VERSION 5.7 ;
  NOWIREEXTENSIONATPIN ON ;
  DIVIDERCHAR "/" ;
  BUSBITCHARS "[]" ;
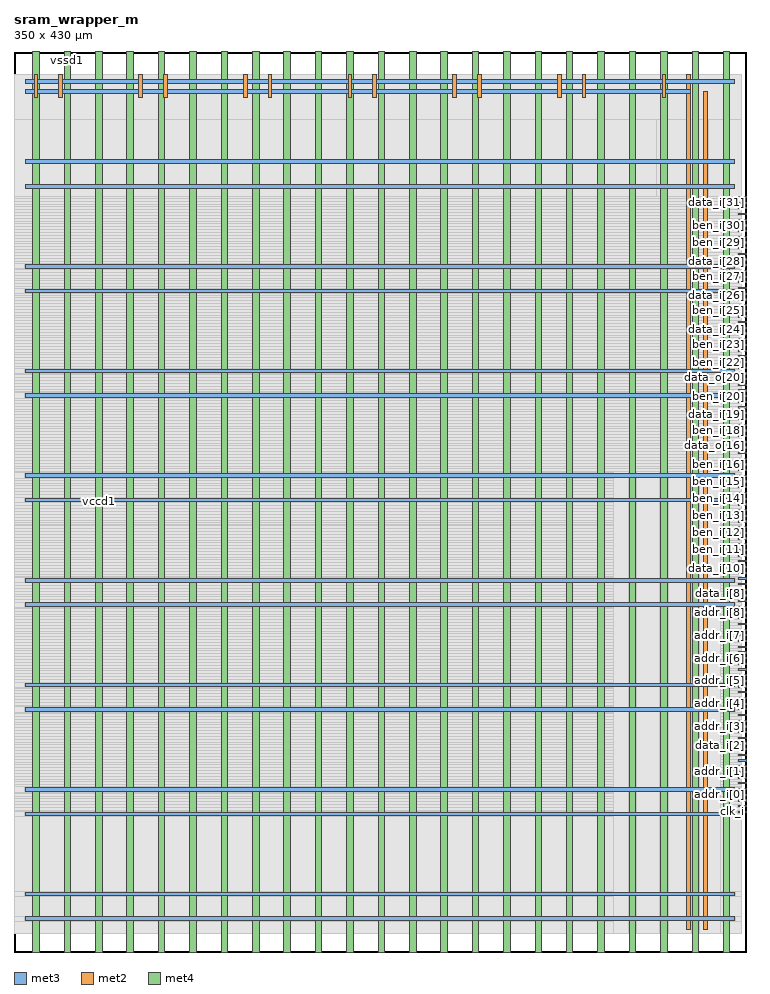
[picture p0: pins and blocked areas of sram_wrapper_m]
MACRO sram_wrapper_m
  CLASS BLOCK ;
  FOREIGN sram_wrapper_m ;
  ORIGIN 0.000 0.000 ;
  SIZE 350.000 BY 430.000 ;
  PIN addr_i[0]
    DIRECTION INPUT ;
    USE SIGNAL ;
    ANTENNAGATEAREA 0.213000 ;
    PORT
      LAYER met3 ;
        RECT 346.000 74.840 350.000 75.440 ;
    END
  END addr_i[0]
  PIN addr_i[1]
    DIRECTION INPUT ;
    USE SIGNAL ;
    ANTENNAGATEAREA 0.213000 ;
    PORT
      LAYER met3 ;
        RECT 346.000 85.720 350.000 86.320 ;
    END
  END addr_i[1]
  PIN addr_i[2]
    DIRECTION INPUT ;
    USE SIGNAL ;
    ANTENNAGATEAREA 0.213000 ;
    PORT
      LAYER met3 ;
        RECT 346.000 96.600 350.000 97.200 ;
    END
  END addr_i[2]
  PIN addr_i[3]
    DIRECTION INPUT ;
    USE SIGNAL ;
    ANTENNAGATEAREA 0.213000 ;
    PORT
      LAYER met3 ;
        RECT 346.000 107.480 350.000 108.080 ;
    END
  END addr_i[3]
  PIN addr_i[4]
    DIRECTION INPUT ;
    USE SIGNAL ;
    ANTENNAGATEAREA 0.159000 ;
    PORT
      LAYER met3 ;
        RECT 346.000 118.360 350.000 118.960 ;
    END
  END addr_i[4]
  PIN addr_i[5]
    DIRECTION INPUT ;
    USE SIGNAL ;
    ANTENNAGATEAREA 0.159000 ;
    PORT
      LAYER met3 ;
        RECT 346.000 129.240 350.000 129.840 ;
    END
  END addr_i[5]
  PIN addr_i[6]
    DIRECTION INPUT ;
    USE SIGNAL ;
    ANTENNAGATEAREA 0.159000 ;
    PORT
      LAYER met3 ;
        RECT 346.000 140.120 350.000 140.720 ;
    END
  END addr_i[6]
  PIN addr_i[7]
    DIRECTION INPUT ;
    USE SIGNAL ;
    ANTENNAGATEAREA 0.159000 ;
    PORT
      LAYER met3 ;
        RECT 346.000 151.000 350.000 151.600 ;
    END
  END addr_i[7]
  PIN addr_i[8]
    DIRECTION INPUT ;
    USE SIGNAL ;
    ANTENNAGATEAREA 0.159000 ;
    PORT
      LAYER met3 ;
        RECT 346.000 161.880 350.000 162.480 ;
    END
  END addr_i[8]
  PIN addr_i[9]
    DIRECTION INPUT ;
    USE SIGNAL ;
    ANTENNAGATEAREA 0.159000 ;
    PORT
      LAYER met3 ;
        RECT 346.000 172.760 350.000 173.360 ;
    END
  END addr_i[9]
  PIN ben_i[0]
    DIRECTION INPUT ;
    USE SIGNAL ;
    ANTENNAGATEAREA 0.159000 ;
    PORT
      LAYER met3 ;
        RECT 346.000 77.560 350.000 78.160 ;
    END
  END ben_i[0]
  PIN ben_i[10]
    DIRECTION INPUT ;
    USE SIGNAL ;
    ANTENNAGATEAREA 0.159000 ;
    PORT
      LAYER met3 ;
        RECT 346.000 183.640 350.000 184.240 ;
    END
  END ben_i[10]
  PIN ben_i[11]
    DIRECTION INPUT ;
    USE SIGNAL ;
    ANTENNAGATEAREA 0.213000 ;
    PORT
      LAYER met3 ;
        RECT 346.000 191.800 350.000 192.400 ;
    END
  END ben_i[11]
  PIN ben_i[12]
    DIRECTION INPUT ;
    USE SIGNAL ;
    ANTENNAGATEAREA 0.213000 ;
    PORT
      LAYER met3 ;
        RECT 346.000 199.960 350.000 200.560 ;
    END
  END ben_i[12]
  PIN ben_i[13]
    DIRECTION INPUT ;
    USE SIGNAL ;
    ANTENNAGATEAREA 0.213000 ;
    PORT
      LAYER met3 ;
        RECT 346.000 208.120 350.000 208.720 ;
    END
  END ben_i[13]
  PIN ben_i[14]
    DIRECTION INPUT ;
    USE SIGNAL ;
    ANTENNAGATEAREA 0.213000 ;
    PORT
      LAYER met3 ;
        RECT 346.000 216.280 350.000 216.880 ;
    END
  END ben_i[14]
  PIN ben_i[15]
    DIRECTION INPUT ;
    USE SIGNAL ;
    ANTENNAGATEAREA 0.213000 ;
    PORT
      LAYER met3 ;
        RECT 346.000 224.440 350.000 225.040 ;
    END
  END ben_i[15]
  PIN ben_i[16]
    DIRECTION INPUT ;
    USE SIGNAL ;
    ANTENNAGATEAREA 0.159000 ;
    PORT
      LAYER met3 ;
        RECT 346.000 232.600 350.000 233.200 ;
    END
  END ben_i[16]
  PIN ben_i[17]
    DIRECTION INPUT ;
    USE SIGNAL ;
    ANTENNAGATEAREA 0.213000 ;
    PORT
      LAYER met3 ;
        RECT 346.000 240.760 350.000 241.360 ;
    END
  END ben_i[17]
  PIN ben_i[18]
    DIRECTION INPUT ;
    USE SIGNAL ;
    ANTENNAGATEAREA 0.213000 ;
    PORT
      LAYER met3 ;
        RECT 346.000 248.920 350.000 249.520 ;
    END
  END ben_i[18]
  PIN ben_i[19]
    DIRECTION INPUT ;
    USE SIGNAL ;
    ANTENNAGATEAREA 0.213000 ;
    PORT
      LAYER met3 ;
        RECT 346.000 257.080 350.000 257.680 ;
    END
  END ben_i[19]
  PIN ben_i[1]
    DIRECTION INPUT ;
    USE SIGNAL ;
    ANTENNAGATEAREA 0.159000 ;
    PORT
      LAYER met3 ;
        RECT 346.000 88.440 350.000 89.040 ;
    END
  END ben_i[1]
  PIN ben_i[20]
    DIRECTION INPUT ;
    USE SIGNAL ;
    ANTENNAGATEAREA 0.213000 ;
    PORT
      LAYER met3 ;
        RECT 346.000 265.240 350.000 265.840 ;
    END
  END ben_i[20]
  PIN ben_i[21]
    DIRECTION INPUT ;
    USE SIGNAL ;
    ANTENNAGATEAREA 0.213000 ;
    PORT
      LAYER met3 ;
        RECT 346.000 273.400 350.000 274.000 ;
    END
  END ben_i[21]
  PIN ben_i[22]
    DIRECTION INPUT ;
    USE SIGNAL ;
    ANTENNAGATEAREA 0.213000 ;
    PORT
      LAYER met3 ;
        RECT 346.000 281.560 350.000 282.160 ;
    END
  END ben_i[22]
  PIN ben_i[23]
    DIRECTION INPUT ;
    USE SIGNAL ;
    ANTENNAGATEAREA 0.213000 ;
    PORT
      LAYER met3 ;
        RECT 346.000 289.720 350.000 290.320 ;
    END
  END ben_i[23]
  PIN ben_i[24]
    DIRECTION INPUT ;
    USE SIGNAL ;
    ANTENNAGATEAREA 0.213000 ;
    PORT
      LAYER met3 ;
        RECT 346.000 297.880 350.000 298.480 ;
    END
  END ben_i[24]
  PIN ben_i[25]
    DIRECTION INPUT ;
    USE SIGNAL ;
    ANTENNAGATEAREA 0.159000 ;
    PORT
      LAYER met3 ;
        RECT 346.000 306.040 350.000 306.640 ;
    END
  END ben_i[25]
  PIN ben_i[26]
    DIRECTION INPUT ;
    USE SIGNAL ;
    ANTENNAGATEAREA 0.159000 ;
    PORT
      LAYER met3 ;
        RECT 346.000 314.200 350.000 314.800 ;
    END
  END ben_i[26]
  PIN ben_i[27]
    DIRECTION INPUT ;
    USE SIGNAL ;
    ANTENNAGATEAREA 0.159000 ;
    PORT
      LAYER met3 ;
        RECT 346.000 322.360 350.000 322.960 ;
    END
  END ben_i[27]
  PIN ben_i[28]
    DIRECTION INPUT ;
    USE SIGNAL ;
    ANTENNAGATEAREA 0.159000 ;
    PORT
      LAYER met3 ;
        RECT 346.000 330.520 350.000 331.120 ;
    END
  END ben_i[28]
  PIN ben_i[29]
    DIRECTION INPUT ;
    USE SIGNAL ;
    ANTENNAGATEAREA 0.159000 ;
    PORT
      LAYER met3 ;
        RECT 346.000 338.680 350.000 339.280 ;
    END
  END ben_i[29]
  PIN ben_i[2]
    DIRECTION INPUT ;
    USE SIGNAL ;
    ANTENNAGATEAREA 0.159000 ;
    PORT
      LAYER met3 ;
        RECT 346.000 99.320 350.000 99.920 ;
    END
  END ben_i[2]
  PIN ben_i[30]
    DIRECTION INPUT ;
    USE SIGNAL ;
    ANTENNAGATEAREA 0.159000 ;
    PORT
      LAYER met3 ;
        RECT 346.000 346.840 350.000 347.440 ;
    END
  END ben_i[30]
  PIN ben_i[31]
    DIRECTION INPUT ;
    USE SIGNAL ;
    ANTENNAGATEAREA 0.159000 ;
    PORT
      LAYER met3 ;
        RECT 346.000 355.000 350.000 355.600 ;
    END
  END ben_i[31]
  PIN ben_i[3]
    DIRECTION INPUT ;
    USE SIGNAL ;
    ANTENNAGATEAREA 0.159000 ;
    PORT
      LAYER met3 ;
        RECT 346.000 110.200 350.000 110.800 ;
    END
  END ben_i[3]
  PIN ben_i[4]
    DIRECTION INPUT ;
    USE SIGNAL ;
    ANTENNAGATEAREA 0.159000 ;
    PORT
      LAYER met3 ;
        RECT 346.000 121.080 350.000 121.680 ;
    END
  END ben_i[4]
  PIN ben_i[5]
    DIRECTION INPUT ;
    USE SIGNAL ;
    ANTENNAGATEAREA 0.213000 ;
    PORT
      LAYER met3 ;
        RECT 346.000 131.960 350.000 132.560 ;
    END
  END ben_i[5]
  PIN ben_i[6]
    DIRECTION INPUT ;
    USE SIGNAL ;
    ANTENNAGATEAREA 0.159000 ;
    PORT
      LAYER met3 ;
        RECT 346.000 142.840 350.000 143.440 ;
    END
  END ben_i[6]
  PIN ben_i[7]
    DIRECTION INPUT ;
    USE SIGNAL ;
    ANTENNAGATEAREA 0.159000 ;
    PORT
      LAYER met3 ;
        RECT 346.000 153.720 350.000 154.320 ;
    END
  END ben_i[7]
  PIN ben_i[8]
    DIRECTION INPUT ;
    USE SIGNAL ;
    ANTENNAGATEAREA 0.159000 ;
    PORT
      LAYER met3 ;
        RECT 346.000 164.600 350.000 165.200 ;
    END
  END ben_i[8]
  PIN ben_i[9]
    DIRECTION INPUT ;
    USE SIGNAL ;
    ANTENNAGATEAREA 0.159000 ;
    PORT
      LAYER met3 ;
        RECT 346.000 175.480 350.000 176.080 ;
    END
  END ben_i[9]
  PIN clk_i
    DIRECTION INPUT ;
    USE SIGNAL ;
    PORT
      LAYER met3 ;
        RECT 346.000 66.680 350.000 67.280 ;
    END
  END clk_i
  PIN data_i[0]
    DIRECTION INPUT ;
    USE SIGNAL ;
    ANTENNAGATEAREA 0.159000 ;
    PORT
      LAYER met3 ;
        RECT 346.000 80.280 350.000 80.880 ;
    END
  END data_i[0]
  PIN data_i[10]
    DIRECTION INPUT ;
    USE SIGNAL ;
    ANTENNAGATEAREA 0.159000 ;
    PORT
      LAYER met3 ;
        RECT 346.000 186.360 350.000 186.960 ;
    END
  END data_i[10]
  PIN data_i[11]
    DIRECTION INPUT ;
    USE SIGNAL ;
    ANTENNAGATEAREA 0.159000 ;
    PORT
      LAYER met3 ;
        RECT 346.000 194.520 350.000 195.120 ;
    END
  END data_i[11]
  PIN data_i[12]
    DIRECTION INPUT ;
    USE SIGNAL ;
    ANTENNAGATEAREA 0.213000 ;
    PORT
      LAYER met3 ;
        RECT 346.000 202.680 350.000 203.280 ;
    END
  END data_i[12]
  PIN data_i[13]
    DIRECTION INPUT ;
    USE SIGNAL ;
    ANTENNAGATEAREA 0.213000 ;
    PORT
      LAYER met3 ;
        RECT 346.000 210.840 350.000 211.440 ;
    END
  END data_i[13]
  PIN data_i[14]
    DIRECTION INPUT ;
    USE SIGNAL ;
    ANTENNAGATEAREA 0.213000 ;
    PORT
      LAYER met3 ;
        RECT 346.000 219.000 350.000 219.600 ;
    END
  END data_i[14]
  PIN data_i[15]
    DIRECTION INPUT ;
    USE SIGNAL ;
    ANTENNAGATEAREA 0.213000 ;
    PORT
      LAYER met3 ;
        RECT 346.000 227.160 350.000 227.760 ;
    END
  END data_i[15]
  PIN data_i[16]
    DIRECTION INPUT ;
    USE SIGNAL ;
    ANTENNAGATEAREA 0.213000 ;
    PORT
      LAYER met3 ;
        RECT 346.000 235.320 350.000 235.920 ;
    END
  END data_i[16]
  PIN data_i[17]
    DIRECTION INPUT ;
    USE SIGNAL ;
    ANTENNAGATEAREA 0.213000 ;
    PORT
      LAYER met3 ;
        RECT 346.000 243.480 350.000 244.080 ;
    END
  END data_i[17]
  PIN data_i[18]
    DIRECTION INPUT ;
    USE SIGNAL ;
    ANTENNAGATEAREA 0.213000 ;
    PORT
      LAYER met3 ;
        RECT 346.000 251.640 350.000 252.240 ;
    END
  END data_i[18]
  PIN data_i[19]
    DIRECTION INPUT ;
    USE SIGNAL ;
    ANTENNAGATEAREA 0.213000 ;
    PORT
      LAYER met3 ;
        RECT 346.000 259.800 350.000 260.400 ;
    END
  END data_i[19]
  PIN data_i[1]
    DIRECTION INPUT ;
    USE SIGNAL ;
    ANTENNAGATEAREA 0.159000 ;
    PORT
      LAYER met3 ;
        RECT 346.000 91.160 350.000 91.760 ;
    END
  END data_i[1]
  PIN data_i[20]
    DIRECTION INPUT ;
    USE SIGNAL ;
    ANTENNAGATEAREA 0.213000 ;
    PORT
      LAYER met3 ;
        RECT 346.000 267.960 350.000 268.560 ;
    END
  END data_i[20]
  PIN data_i[21]
    DIRECTION INPUT ;
    USE SIGNAL ;
    ANTENNAGATEAREA 0.213000 ;
    PORT
      LAYER met3 ;
        RECT 346.000 276.120 350.000 276.720 ;
    END
  END data_i[21]
  PIN data_i[22]
    DIRECTION INPUT ;
    USE SIGNAL ;
    ANTENNAGATEAREA 0.213000 ;
    PORT
      LAYER met3 ;
        RECT 346.000 284.280 350.000 284.880 ;
    END
  END data_i[22]
  PIN data_i[23]
    DIRECTION INPUT ;
    USE SIGNAL ;
    ANTENNAGATEAREA 0.213000 ;
    PORT
      LAYER met3 ;
        RECT 346.000 292.440 350.000 293.040 ;
    END
  END data_i[23]
  PIN data_i[24]
    DIRECTION INPUT ;
    USE SIGNAL ;
    ANTENNAGATEAREA 0.213000 ;
    PORT
      LAYER met3 ;
        RECT 346.000 300.600 350.000 301.200 ;
    END
  END data_i[24]
  PIN data_i[25]
    DIRECTION INPUT ;
    USE SIGNAL ;
    ANTENNAGATEAREA 0.213000 ;
    PORT
      LAYER met3 ;
        RECT 346.000 308.760 350.000 309.360 ;
    END
  END data_i[25]
  PIN data_i[26]
    DIRECTION INPUT ;
    USE SIGNAL ;
    ANTENNAGATEAREA 0.213000 ;
    PORT
      LAYER met3 ;
        RECT 346.000 316.920 350.000 317.520 ;
    END
  END data_i[26]
  PIN data_i[27]
    DIRECTION INPUT ;
    USE SIGNAL ;
    ANTENNAGATEAREA 0.213000 ;
    PORT
      LAYER met3 ;
        RECT 346.000 325.080 350.000 325.680 ;
    END
  END data_i[27]
  PIN data_i[28]
    DIRECTION INPUT ;
    USE SIGNAL ;
    ANTENNAGATEAREA 0.159000 ;
    PORT
      LAYER met3 ;
        RECT 346.000 333.240 350.000 333.840 ;
    END
  END data_i[28]
  PIN data_i[29]
    DIRECTION INPUT ;
    USE SIGNAL ;
    ANTENNAGATEAREA 0.159000 ;
    PORT
      LAYER met3 ;
        RECT 346.000 341.400 350.000 342.000 ;
    END
  END data_i[29]
  PIN data_i[2]
    DIRECTION INPUT ;
    USE SIGNAL ;
    ANTENNAGATEAREA 0.159000 ;
    PORT
      LAYER met3 ;
        RECT 346.000 102.040 350.000 102.640 ;
    END
  END data_i[2]
  PIN data_i[30]
    DIRECTION INPUT ;
    USE SIGNAL ;
    ANTENNAGATEAREA 0.159000 ;
    PORT
      LAYER met3 ;
        RECT 346.000 349.560 350.000 350.160 ;
    END
  END data_i[30]
  PIN data_i[31]
    DIRECTION INPUT ;
    USE SIGNAL ;
    ANTENNAGATEAREA 0.159000 ;
    PORT
      LAYER met3 ;
        RECT 346.000 357.720 350.000 358.320 ;
    END
  END data_i[31]
  PIN data_i[3]
    DIRECTION INPUT ;
    USE SIGNAL ;
    ANTENNAGATEAREA 0.159000 ;
    PORT
      LAYER met3 ;
        RECT 346.000 112.920 350.000 113.520 ;
    END
  END data_i[3]
  PIN data_i[4]
    DIRECTION INPUT ;
    USE SIGNAL ;
    ANTENNAGATEAREA 0.213000 ;
    PORT
      LAYER met3 ;
        RECT 346.000 123.800 350.000 124.400 ;
    END
  END data_i[4]
  PIN data_i[5]
    DIRECTION INPUT ;
    USE SIGNAL ;
    ANTENNAGATEAREA 0.213000 ;
    PORT
      LAYER met3 ;
        RECT 346.000 134.680 350.000 135.280 ;
    END
  END data_i[5]
  PIN data_i[6]
    DIRECTION INPUT ;
    USE SIGNAL ;
    ANTENNAGATEAREA 0.159000 ;
    PORT
      LAYER met3 ;
        RECT 346.000 145.560 350.000 146.160 ;
    END
  END data_i[6]
  PIN data_i[7]
    DIRECTION INPUT ;
    USE SIGNAL ;
    ANTENNAGATEAREA 0.159000 ;
    PORT
      LAYER met3 ;
        RECT 346.000 156.440 350.000 157.040 ;
    END
  END data_i[7]
  PIN data_i[8]
    DIRECTION INPUT ;
    USE SIGNAL ;
    ANTENNAGATEAREA 0.159000 ;
    PORT
      LAYER met3 ;
        RECT 346.000 167.320 350.000 167.920 ;
    END
  END data_i[8]
  PIN data_i[9]
    DIRECTION INPUT ;
    USE SIGNAL ;
    ANTENNAGATEAREA 0.159000 ;
    PORT
      LAYER met3 ;
        RECT 346.000 178.200 350.000 178.800 ;
    END
  END data_i[9]
  PIN data_o[0]
    DIRECTION OUTPUT TRISTATE ;
    USE SIGNAL ;
    ANTENNADIFFAREA 0.445500 ;
    PORT
      LAYER met3 ;
        RECT 346.000 83.000 350.000 83.600 ;
    END
  END data_o[0]
  PIN data_o[10]
    DIRECTION OUTPUT TRISTATE ;
    USE SIGNAL ;
    ANTENNADIFFAREA 0.445500 ;
    PORT
      LAYER met3 ;
        RECT 346.000 189.080 350.000 189.680 ;
    END
  END data_o[10]
  PIN data_o[11]
    DIRECTION OUTPUT TRISTATE ;
    USE SIGNAL ;
    ANTENNADIFFAREA 0.445500 ;
    PORT
      LAYER met3 ;
        RECT 346.000 197.240 350.000 197.840 ;
    END
  END data_o[11]
  PIN data_o[12]
    DIRECTION OUTPUT TRISTATE ;
    USE SIGNAL ;
    ANTENNADIFFAREA 0.795200 ;
    PORT
      LAYER met3 ;
        RECT 346.000 205.400 350.000 206.000 ;
    END
  END data_o[12]
  PIN data_o[13]
    DIRECTION OUTPUT TRISTATE ;
    USE SIGNAL ;
    ANTENNADIFFAREA 0.795200 ;
    PORT
      LAYER met3 ;
        RECT 346.000 213.560 350.000 214.160 ;
    END
  END data_o[13]
  PIN data_o[14]
    DIRECTION OUTPUT TRISTATE ;
    USE SIGNAL ;
    ANTENNADIFFAREA 0.445500 ;
    PORT
      LAYER met3 ;
        RECT 346.000 221.720 350.000 222.320 ;
    END
  END data_o[14]
  PIN data_o[15]
    DIRECTION OUTPUT TRISTATE ;
    USE SIGNAL ;
    ANTENNADIFFAREA 0.445500 ;
    PORT
      LAYER met3 ;
        RECT 346.000 229.880 350.000 230.480 ;
    END
  END data_o[15]
  PIN data_o[16]
    DIRECTION OUTPUT TRISTATE ;
    USE SIGNAL ;
    ANTENNADIFFAREA 0.445500 ;
    PORT
      LAYER met3 ;
        RECT 346.000 238.040 350.000 238.640 ;
    END
  END data_o[16]
  PIN data_o[17]
    DIRECTION OUTPUT TRISTATE ;
    USE SIGNAL ;
    ANTENNADIFFAREA 0.795200 ;
    PORT
      LAYER met3 ;
        RECT 346.000 246.200 350.000 246.800 ;
    END
  END data_o[17]
  PIN data_o[18]
    DIRECTION OUTPUT TRISTATE ;
    USE SIGNAL ;
    ANTENNADIFFAREA 0.795200 ;
    PORT
      LAYER met3 ;
        RECT 346.000 254.360 350.000 254.960 ;
    END
  END data_o[18]
  PIN data_o[19]
    DIRECTION OUTPUT TRISTATE ;
    USE SIGNAL ;
    ANTENNADIFFAREA 0.445500 ;
    PORT
      LAYER met3 ;
        RECT 346.000 262.520 350.000 263.120 ;
    END
  END data_o[19]
  PIN data_o[1]
    DIRECTION OUTPUT TRISTATE ;
    USE SIGNAL ;
    ANTENNADIFFAREA 0.795200 ;
    PORT
      LAYER met3 ;
        RECT 346.000 93.880 350.000 94.480 ;
    END
  END data_o[1]
  PIN data_o[20]
    DIRECTION OUTPUT TRISTATE ;
    USE SIGNAL ;
    ANTENNADIFFAREA 0.445500 ;
    PORT
      LAYER met3 ;
        RECT 346.000 270.680 350.000 271.280 ;
    END
  END data_o[20]
  PIN data_o[21]
    DIRECTION OUTPUT TRISTATE ;
    USE SIGNAL ;
    ANTENNADIFFAREA 0.445500 ;
    PORT
      LAYER met3 ;
        RECT 346.000 278.840 350.000 279.440 ;
    END
  END data_o[21]
  PIN data_o[22]
    DIRECTION OUTPUT TRISTATE ;
    USE SIGNAL ;
    ANTENNADIFFAREA 0.445500 ;
    PORT
      LAYER met3 ;
        RECT 346.000 287.000 350.000 287.600 ;
    END
  END data_o[22]
  PIN data_o[23]
    DIRECTION OUTPUT TRISTATE ;
    USE SIGNAL ;
    ANTENNADIFFAREA 0.795200 ;
    PORT
      LAYER met3 ;
        RECT 346.000 295.160 350.000 295.760 ;
    END
  END data_o[23]
  PIN data_o[24]
    DIRECTION OUTPUT TRISTATE ;
    USE SIGNAL ;
    ANTENNADIFFAREA 0.445500 ;
    PORT
      LAYER met3 ;
        RECT 346.000 303.320 350.000 303.920 ;
    END
  END data_o[24]
  PIN data_o[25]
    DIRECTION OUTPUT TRISTATE ;
    USE SIGNAL ;
    ANTENNADIFFAREA 0.445500 ;
    PORT
      LAYER met3 ;
        RECT 346.000 311.480 350.000 312.080 ;
    END
  END data_o[25]
  PIN data_o[26]
    DIRECTION OUTPUT TRISTATE ;
    USE SIGNAL ;
    ANTENNADIFFAREA 0.445500 ;
    PORT
      LAYER met3 ;
        RECT 346.000 319.640 350.000 320.240 ;
    END
  END data_o[26]
  PIN data_o[27]
    DIRECTION OUTPUT TRISTATE ;
    USE SIGNAL ;
    ANTENNADIFFAREA 0.445500 ;
    PORT
      LAYER met3 ;
        RECT 346.000 327.800 350.000 328.400 ;
    END
  END data_o[27]
  PIN data_o[28]
    DIRECTION OUTPUT TRISTATE ;
    USE SIGNAL ;
    ANTENNADIFFAREA 0.795200 ;
    PORT
      LAYER met3 ;
        RECT 346.000 335.960 350.000 336.560 ;
    END
  END data_o[28]
  PIN data_o[29]
    DIRECTION OUTPUT TRISTATE ;
    USE SIGNAL ;
    ANTENNADIFFAREA 0.795200 ;
    PORT
      LAYER met3 ;
        RECT 346.000 344.120 350.000 344.720 ;
    END
  END data_o[29]
  PIN data_o[2]
    DIRECTION OUTPUT TRISTATE ;
    USE SIGNAL ;
    ANTENNADIFFAREA 0.445500 ;
    PORT
      LAYER met3 ;
        RECT 346.000 104.760 350.000 105.360 ;
    END
  END data_o[2]
  PIN data_o[30]
    DIRECTION OUTPUT TRISTATE ;
    USE SIGNAL ;
    ANTENNADIFFAREA 0.445500 ;
    PORT
      LAYER met3 ;
        RECT 346.000 352.280 350.000 352.880 ;
    END
  END data_o[30]
  PIN data_o[31]
    DIRECTION OUTPUT TRISTATE ;
    USE SIGNAL ;
    ANTENNADIFFAREA 0.445500 ;
    PORT
      LAYER met3 ;
        RECT 346.000 360.440 350.000 361.040 ;
    END
  END data_o[31]
  PIN data_o[3]
    DIRECTION OUTPUT TRISTATE ;
    USE SIGNAL ;
    ANTENNADIFFAREA 0.795200 ;
    PORT
      LAYER met3 ;
        RECT 346.000 115.640 350.000 116.240 ;
    END
  END data_o[3]
  PIN data_o[4]
    DIRECTION OUTPUT TRISTATE ;
    USE SIGNAL ;
    ANTENNADIFFAREA 0.445500 ;
    PORT
      LAYER met3 ;
        RECT 346.000 126.520 350.000 127.120 ;
    END
  END data_o[4]
  PIN data_o[5]
    DIRECTION OUTPUT TRISTATE ;
    USE SIGNAL ;
    ANTENNADIFFAREA 0.795200 ;
    PORT
      LAYER met3 ;
        RECT 346.000 137.400 350.000 138.000 ;
    END
  END data_o[5]
  PIN data_o[6]
    DIRECTION OUTPUT TRISTATE ;
    USE SIGNAL ;
    ANTENNADIFFAREA 0.445500 ;
    PORT
      LAYER met3 ;
        RECT 346.000 148.280 350.000 148.880 ;
    END
  END data_o[6]
  PIN data_o[7]
    DIRECTION OUTPUT TRISTATE ;
    USE SIGNAL ;
    ANTENNADIFFAREA 0.445500 ;
    PORT
      LAYER met3 ;
        RECT 346.000 159.160 350.000 159.760 ;
    END
  END data_o[7]
  PIN data_o[8]
    DIRECTION OUTPUT TRISTATE ;
    USE SIGNAL ;
    ANTENNADIFFAREA 0.795200 ;
    PORT
      LAYER met3 ;
        RECT 346.000 170.040 350.000 170.640 ;
    END
  END data_o[8]
  PIN data_o[9]
    DIRECTION OUTPUT TRISTATE ;
    USE SIGNAL ;
    ANTENNADIFFAREA 0.445500 ;
    PORT
      LAYER met3 ;
        RECT 346.000 180.920 350.000 181.520 ;
    END
  END data_o[9]
  PIN en_i
    DIRECTION INPUT ;
    USE SIGNAL ;
    ANTENNAGATEAREA 0.213000 ;
    PORT
      LAYER met3 ;
        RECT 346.000 69.400 350.000 70.000 ;
    END
  END en_i
  PIN read_en_i
    DIRECTION INPUT ;
    USE SIGNAL ;
    ANTENNAGATEAREA 0.213000 ;
    PORT
      LAYER met3 ;
        RECT 346.000 72.120 350.000 72.720 ;
    END
  END read_en_i
  PIN vccd1
    DIRECTION INOUT ;
    USE POWER ;
    PORT
      LAYER met2 ;
        RECT 9.640 408.150 11.400 419.120 ;
    END
    PORT
      LAYER met2 ;
        RECT 59.640 408.150 61.400 419.120 ;
    END
    PORT
      LAYER met2 ;
        RECT 109.640 408.150 111.400 419.120 ;
    END
    PORT
      LAYER met2 ;
        RECT 159.640 408.150 161.400 419.120 ;
    END
    PORT
      LAYER met2 ;
        RECT 209.640 408.150 211.400 419.120 ;
    END
    PORT
      LAYER met2 ;
        RECT 259.640 408.150 261.400 419.120 ;
    END
    PORT
      LAYER met2 ;
        RECT 309.640 408.150 311.400 419.120 ;
    END
    PORT
      LAYER met3 ;
        RECT 5.280 15.000 344.320 16.760 ;
    END
    PORT
      LAYER met3 ;
        RECT 5.280 65.000 344.320 66.760 ;
    END
    PORT
      LAYER met3 ;
        RECT 5.280 115.000 344.320 116.760 ;
    END
    PORT
      LAYER met3 ;
        RECT 5.280 165.000 344.320 166.760 ;
    END
    PORT
      LAYER met3 ;
        RECT 5.280 215.000 344.320 216.760 ;
    END
    PORT
      LAYER met3 ;
        RECT 5.280 265.000 344.320 266.760 ;
    END
    PORT
      LAYER met3 ;
        RECT 5.280 315.000 344.320 316.760 ;
    END
    PORT
      LAYER met3 ;
        RECT 5.280 365.000 344.320 366.760 ;
    END
    PORT
      LAYER met3 ;
        RECT 5.280 415.000 344.320 416.760 ;
    END
    PORT
      LAYER met4 ;
        RECT 8.970 0.000 12.070 430.000 ;
    END
    PORT
      LAYER met4 ;
        RECT 38.970 0.000 42.070 430.000 ;
    END
    PORT
      LAYER met4 ;
        RECT 68.970 0.000 72.070 430.000 ;
    END
    PORT
      LAYER met4 ;
        RECT 98.970 0.000 102.070 430.000 ;
    END
    PORT
      LAYER met4 ;
        RECT 128.970 0.000 132.070 430.000 ;
    END
    PORT
      LAYER met4 ;
        RECT 158.970 0.000 162.070 430.000 ;
    END
    PORT
      LAYER met4 ;
        RECT 188.970 0.000 192.070 430.000 ;
    END
    PORT
      LAYER met4 ;
        RECT 218.970 0.000 222.070 430.000 ;
    END
    PORT
      LAYER met4 ;
        RECT 248.970 0.000 252.070 430.000 ;
    END
    PORT
      LAYER met4 ;
        RECT 278.970 0.000 282.070 430.000 ;
    END
    PORT
      LAYER met4 ;
        RECT 308.970 0.000 312.070 430.000 ;
    END
    PORT
      LAYER met4 ;
        RECT 338.970 0.000 342.070 430.000 ;
    END
    PORT
      LAYER met2 ;
        RECT 329.630 10.640 331.390 410.960 ;
    END
  END vccd1
  PIN vssd1
    DIRECTION INOUT ;
    USE GROUND ;
    PORT
      LAYER met2 ;
        RECT 21.400 408.150 23.160 419.120 ;
    END
    PORT
      LAYER met2 ;
        RECT 71.400 408.150 73.160 419.120 ;
    END
    PORT
      LAYER met2 ;
        RECT 121.400 408.150 123.160 419.120 ;
    END
    PORT
      LAYER met2 ;
        RECT 171.400 408.150 173.160 419.120 ;
    END
    PORT
      LAYER met2 ;
        RECT 221.400 408.150 223.160 419.120 ;
    END
    PORT
      LAYER met2 ;
        RECT 271.400 408.150 273.160 419.120 ;
    END
    PORT
      LAYER met2 ;
        RECT 321.400 10.640 323.160 419.120 ;
    END
    PORT
      LAYER met3 ;
        RECT 5.280 26.760 344.320 28.520 ;
    END
    PORT
      LAYER met3 ;
        RECT 5.280 76.760 344.320 78.520 ;
    END
    PORT
      LAYER met3 ;
        RECT 5.280 126.760 344.320 128.520 ;
    END
    PORT
      LAYER met3 ;
        RECT 5.280 176.760 344.320 178.520 ;
    END
    PORT
      LAYER met3 ;
        RECT 5.280 226.760 344.320 228.520 ;
    END
    PORT
      LAYER met3 ;
        RECT 5.280 276.760 344.320 278.520 ;
    END
    PORT
      LAYER met3 ;
        RECT 5.280 326.760 344.320 328.520 ;
    END
    PORT
      LAYER met3 ;
        RECT 5.280 376.760 344.320 378.520 ;
    END
    PORT
      LAYER met4 ;
        RECT 23.970 0.000 27.070 430.000 ;
    END
    PORT
      LAYER met4 ;
        RECT 53.970 0.000 57.070 430.000 ;
    END
    PORT
      LAYER met4 ;
        RECT 83.970 0.000 87.070 430.000 ;
    END
    PORT
      LAYER met4 ;
        RECT 113.970 0.000 117.070 430.000 ;
    END
    PORT
      LAYER met4 ;
        RECT 143.970 0.000 147.070 430.000 ;
    END
    PORT
      LAYER met4 ;
        RECT 173.970 0.000 177.070 430.000 ;
    END
    PORT
      LAYER met4 ;
        RECT 203.970 0.000 207.070 430.000 ;
    END
    PORT
      LAYER met4 ;
        RECT 233.970 0.000 237.070 430.000 ;
    END
    PORT
      LAYER met4 ;
        RECT 263.970 0.000 267.070 430.000 ;
    END
    PORT
      LAYER met4 ;
        RECT 293.970 0.000 297.070 430.000 ;
    END
    PORT
      LAYER met4 ;
        RECT 323.970 0.000 327.070 430.000 ;
    END
    PORT
      LAYER met3 ;
        RECT 5.280 410.180 323.160 411.940 ;
    END
  END vssd1
  OBS
      LAYER li1 ;
        RECT 5.520 10.795 344.080 418.965 ;
      LAYER met1 ;
        RECT 0.000 397.870 347.690 419.120 ;
      LAYER met1 ;
        RECT 0.000 10.000 304.775 397.870 ;
      LAYER met1 ;
        RECT 304.775 10.000 347.690 397.870 ;
      LAYER met2 ;
        RECT 0.000 10.000 306.775 397.870 ;
      LAYER met2 ;
        RECT 306.775 10.360 321.120 397.870 ;
        RECT 323.440 10.360 329.350 397.870 ;
        RECT 331.670 10.360 347.670 397.870 ;
        RECT 306.775 10.000 347.670 10.360 ;
        RECT 0.000 8.995 347.670 10.000 ;
      LAYER met3 ;
        RECT 0.000 360.040 345.600 360.905 ;
        RECT 0.000 358.720 347.695 360.040 ;
        RECT 0.000 357.320 345.600 358.720 ;
        RECT 0.000 356.000 347.695 357.320 ;
        RECT 0.000 354.600 345.600 356.000 ;
        RECT 0.000 353.280 347.695 354.600 ;
        RECT 0.000 351.880 345.600 353.280 ;
        RECT 0.000 350.560 347.695 351.880 ;
        RECT 0.000 349.160 345.600 350.560 ;
        RECT 0.000 347.840 347.695 349.160 ;
        RECT 0.000 346.440 345.600 347.840 ;
        RECT 0.000 345.120 347.695 346.440 ;
        RECT 0.000 343.720 345.600 345.120 ;
        RECT 0.000 342.400 347.695 343.720 ;
        RECT 0.000 341.000 345.600 342.400 ;
        RECT 0.000 339.680 347.695 341.000 ;
        RECT 0.000 338.280 345.600 339.680 ;
        RECT 0.000 336.960 347.695 338.280 ;
        RECT 0.000 335.560 345.600 336.960 ;
        RECT 0.000 334.240 347.695 335.560 ;
        RECT 0.000 332.840 345.600 334.240 ;
        RECT 0.000 331.520 347.695 332.840 ;
        RECT 0.000 330.120 345.600 331.520 ;
        RECT 0.000 328.920 347.695 330.120 ;
        RECT 0.000 326.360 4.880 328.920 ;
        RECT 344.720 328.800 347.695 328.920 ;
        RECT 344.720 327.400 345.600 328.800 ;
        RECT 344.720 326.360 347.695 327.400 ;
        RECT 0.000 326.080 347.695 326.360 ;
        RECT 0.000 324.680 345.600 326.080 ;
        RECT 0.000 323.360 347.695 324.680 ;
        RECT 0.000 321.960 345.600 323.360 ;
        RECT 0.000 320.640 347.695 321.960 ;
        RECT 0.000 319.240 345.600 320.640 ;
        RECT 0.000 317.920 347.695 319.240 ;
        RECT 0.000 317.160 345.600 317.920 ;
        RECT 0.000 314.600 4.880 317.160 ;
        RECT 344.720 316.520 345.600 317.160 ;
        RECT 344.720 315.200 347.695 316.520 ;
        RECT 344.720 314.600 345.600 315.200 ;
        RECT 0.000 313.800 345.600 314.600 ;
        RECT 0.000 312.480 347.695 313.800 ;
        RECT 0.000 311.080 345.600 312.480 ;
        RECT 0.000 309.760 347.695 311.080 ;
        RECT 0.000 308.360 345.600 309.760 ;
        RECT 0.000 307.040 347.695 308.360 ;
        RECT 0.000 305.640 345.600 307.040 ;
        RECT 0.000 304.320 347.695 305.640 ;
        RECT 0.000 302.920 345.600 304.320 ;
        RECT 0.000 301.600 347.695 302.920 ;
        RECT 0.000 300.200 345.600 301.600 ;
        RECT 0.000 298.880 347.695 300.200 ;
        RECT 0.000 297.480 345.600 298.880 ;
        RECT 0.000 296.160 347.695 297.480 ;
        RECT 0.000 294.760 345.600 296.160 ;
        RECT 0.000 293.440 347.695 294.760 ;
        RECT 0.000 292.040 345.600 293.440 ;
        RECT 0.000 290.720 347.695 292.040 ;
        RECT 0.000 289.320 345.600 290.720 ;
        RECT 0.000 288.000 347.695 289.320 ;
        RECT 0.000 286.600 345.600 288.000 ;
        RECT 0.000 285.280 347.695 286.600 ;
        RECT 0.000 283.880 345.600 285.280 ;
        RECT 0.000 282.560 347.695 283.880 ;
        RECT 0.000 281.160 345.600 282.560 ;
        RECT 0.000 279.840 347.695 281.160 ;
        RECT 0.000 278.920 345.600 279.840 ;
        RECT 0.000 276.360 4.880 278.920 ;
        RECT 344.720 278.440 345.600 278.920 ;
        RECT 344.720 277.120 347.695 278.440 ;
        RECT 344.720 276.360 345.600 277.120 ;
        RECT 0.000 275.720 345.600 276.360 ;
        RECT 0.000 274.400 347.695 275.720 ;
        RECT 0.000 273.000 345.600 274.400 ;
        RECT 0.000 271.680 347.695 273.000 ;
        RECT 0.000 270.280 345.600 271.680 ;
        RECT 0.000 268.960 347.695 270.280 ;
        RECT 0.000 267.560 345.600 268.960 ;
        RECT 0.000 267.160 347.695 267.560 ;
        RECT 0.000 264.600 4.880 267.160 ;
        RECT 344.720 266.240 347.695 267.160 ;
        RECT 344.720 264.840 345.600 266.240 ;
        RECT 344.720 264.600 347.695 264.840 ;
        RECT 0.000 263.520 347.695 264.600 ;
        RECT 0.000 262.120 345.600 263.520 ;
        RECT 0.000 260.800 347.695 262.120 ;
        RECT 0.000 259.400 345.600 260.800 ;
        RECT 0.000 258.080 347.695 259.400 ;
        RECT 0.000 256.680 345.600 258.080 ;
        RECT 0.000 255.360 347.695 256.680 ;
        RECT 0.000 253.960 345.600 255.360 ;
        RECT 0.000 252.640 347.695 253.960 ;
        RECT 0.000 251.240 345.600 252.640 ;
        RECT 0.000 249.920 347.695 251.240 ;
        RECT 0.000 248.520 345.600 249.920 ;
        RECT 0.000 247.200 347.695 248.520 ;
        RECT 0.000 245.800 345.600 247.200 ;
        RECT 0.000 244.480 347.695 245.800 ;
        RECT 0.000 243.080 345.600 244.480 ;
        RECT 0.000 241.760 347.695 243.080 ;
        RECT 0.000 240.360 345.600 241.760 ;
        RECT 0.000 239.040 347.695 240.360 ;
        RECT 0.000 237.640 345.600 239.040 ;
        RECT 0.000 236.320 347.695 237.640 ;
        RECT 0.000 234.920 345.600 236.320 ;
        RECT 0.000 233.600 347.695 234.920 ;
        RECT 0.000 232.200 345.600 233.600 ;
        RECT 0.000 230.880 347.695 232.200 ;
        RECT 0.000 229.480 345.600 230.880 ;
        RECT 0.000 228.920 347.695 229.480 ;
        RECT 0.000 226.360 4.880 228.920 ;
        RECT 344.720 228.160 347.695 228.920 ;
        RECT 344.720 226.760 345.600 228.160 ;
        RECT 344.720 226.360 347.695 226.760 ;
        RECT 0.000 225.440 347.695 226.360 ;
        RECT 0.000 224.040 345.600 225.440 ;
        RECT 0.000 222.720 347.695 224.040 ;
        RECT 0.000 221.320 345.600 222.720 ;
        RECT 0.000 220.000 347.695 221.320 ;
        RECT 0.000 218.600 345.600 220.000 ;
        RECT 0.000 217.280 347.695 218.600 ;
        RECT 0.000 217.160 345.600 217.280 ;
        RECT 0.000 214.600 4.880 217.160 ;
        RECT 344.720 215.880 345.600 217.160 ;
        RECT 344.720 214.600 347.695 215.880 ;
        RECT 0.000 214.560 347.695 214.600 ;
        RECT 0.000 213.160 345.600 214.560 ;
        RECT 0.000 211.840 347.695 213.160 ;
        RECT 0.000 210.440 345.600 211.840 ;
        RECT 0.000 209.120 347.695 210.440 ;
        RECT 0.000 207.720 345.600 209.120 ;
        RECT 0.000 206.400 347.695 207.720 ;
        RECT 0.000 205.000 345.600 206.400 ;
        RECT 0.000 204.100 347.695 205.000 ;
      LAYER met3 ;
        RECT 0.000 203.770 304.590 204.100 ;
      LAYER met3 ;
        RECT 304.590 203.770 347.695 204.100 ;
        RECT 0.000 203.680 347.695 203.770 ;
        RECT 0.000 202.280 345.600 203.680 ;
        RECT 0.000 200.960 347.695 202.280 ;
        RECT 0.000 199.560 345.600 200.960 ;
        RECT 0.000 198.240 347.695 199.560 ;
        RECT 0.000 196.840 345.600 198.240 ;
        RECT 0.000 195.520 347.695 196.840 ;
        RECT 0.000 194.120 345.600 195.520 ;
        RECT 0.000 192.800 347.695 194.120 ;
        RECT 0.000 191.400 345.600 192.800 ;
        RECT 0.000 190.080 347.695 191.400 ;
        RECT 0.000 188.680 345.600 190.080 ;
        RECT 0.000 187.360 347.695 188.680 ;
        RECT 0.000 185.960 345.600 187.360 ;
        RECT 0.000 184.640 347.695 185.960 ;
        RECT 0.000 183.240 345.600 184.640 ;
        RECT 0.000 181.920 347.695 183.240 ;
        RECT 0.000 180.520 345.600 181.920 ;
        RECT 0.000 179.200 347.695 180.520 ;
        RECT 0.000 178.920 345.600 179.200 ;
        RECT 0.000 176.360 4.880 178.920 ;
        RECT 344.720 177.800 345.600 178.920 ;
        RECT 344.720 176.480 347.695 177.800 ;
        RECT 344.720 176.360 345.600 176.480 ;
        RECT 0.000 175.080 345.600 176.360 ;
        RECT 0.000 173.760 347.695 175.080 ;
        RECT 0.000 172.360 345.600 173.760 ;
        RECT 0.000 171.040 347.695 172.360 ;
        RECT 0.000 169.640 345.600 171.040 ;
        RECT 0.000 168.320 347.695 169.640 ;
        RECT 0.000 167.160 345.600 168.320 ;
        RECT 0.000 164.600 4.880 167.160 ;
        RECT 344.720 166.920 345.600 167.160 ;
        RECT 344.720 165.600 347.695 166.920 ;
        RECT 344.720 164.600 345.600 165.600 ;
        RECT 0.000 164.200 345.600 164.600 ;
        RECT 0.000 162.880 347.695 164.200 ;
        RECT 0.000 161.480 345.600 162.880 ;
        RECT 0.000 160.160 347.695 161.480 ;
        RECT 0.000 158.760 345.600 160.160 ;
        RECT 0.000 157.440 347.695 158.760 ;
        RECT 0.000 156.040 345.600 157.440 ;
        RECT 0.000 154.720 347.695 156.040 ;
        RECT 0.000 153.320 345.600 154.720 ;
        RECT 0.000 152.000 347.695 153.320 ;
        RECT 0.000 150.600 345.600 152.000 ;
        RECT 0.000 149.280 347.695 150.600 ;
        RECT 0.000 147.880 345.600 149.280 ;
        RECT 0.000 146.560 347.695 147.880 ;
        RECT 0.000 145.160 345.600 146.560 ;
        RECT 0.000 143.840 347.695 145.160 ;
        RECT 0.000 142.440 345.600 143.840 ;
        RECT 0.000 141.120 347.695 142.440 ;
        RECT 0.000 139.720 345.600 141.120 ;
        RECT 0.000 138.400 347.695 139.720 ;
        RECT 0.000 137.000 345.600 138.400 ;
        RECT 0.000 135.680 347.695 137.000 ;
        RECT 0.000 134.280 345.600 135.680 ;
        RECT 0.000 132.960 347.695 134.280 ;
        RECT 0.000 131.560 345.600 132.960 ;
        RECT 0.000 130.240 347.695 131.560 ;
        RECT 0.000 128.920 345.600 130.240 ;
        RECT 0.000 126.360 4.880 128.920 ;
        RECT 344.720 128.840 345.600 128.920 ;
        RECT 344.720 127.520 347.695 128.840 ;
        RECT 344.720 126.360 345.600 127.520 ;
        RECT 0.000 126.120 345.600 126.360 ;
        RECT 0.000 124.800 347.695 126.120 ;
        RECT 0.000 123.400 345.600 124.800 ;
        RECT 0.000 122.080 347.695 123.400 ;
        RECT 0.000 120.680 345.600 122.080 ;
        RECT 0.000 119.360 347.695 120.680 ;
        RECT 0.000 117.960 345.600 119.360 ;
        RECT 0.000 117.160 347.695 117.960 ;
        RECT 0.000 114.600 4.880 117.160 ;
        RECT 344.720 116.640 347.695 117.160 ;
        RECT 344.720 115.240 345.600 116.640 ;
        RECT 344.720 114.600 347.695 115.240 ;
        RECT 0.000 113.920 347.695 114.600 ;
        RECT 0.000 112.520 345.600 113.920 ;
        RECT 0.000 111.200 347.695 112.520 ;
        RECT 0.000 109.800 345.600 111.200 ;
        RECT 0.000 108.480 347.695 109.800 ;
        RECT 0.000 107.080 345.600 108.480 ;
        RECT 0.000 105.760 347.695 107.080 ;
        RECT 0.000 104.360 345.600 105.760 ;
        RECT 0.000 103.040 347.695 104.360 ;
        RECT 0.000 101.640 345.600 103.040 ;
        RECT 0.000 100.320 347.695 101.640 ;
        RECT 0.000 98.920 345.600 100.320 ;
        RECT 0.000 97.600 347.695 98.920 ;
        RECT 0.000 96.200 345.600 97.600 ;
        RECT 0.000 94.880 347.695 96.200 ;
        RECT 0.000 93.480 345.600 94.880 ;
        RECT 0.000 92.160 347.695 93.480 ;
        RECT 0.000 90.760 345.600 92.160 ;
        RECT 0.000 89.440 347.695 90.760 ;
        RECT 0.000 88.040 345.600 89.440 ;
        RECT 0.000 86.720 347.695 88.040 ;
        RECT 0.000 85.320 345.600 86.720 ;
        RECT 0.000 84.000 347.695 85.320 ;
        RECT 0.000 82.600 345.600 84.000 ;
        RECT 0.000 81.280 347.695 82.600 ;
        RECT 0.000 79.880 345.600 81.280 ;
        RECT 0.000 78.920 347.695 79.880 ;
        RECT 0.000 76.360 4.880 78.920 ;
        RECT 344.720 78.560 347.695 78.920 ;
        RECT 344.720 77.160 345.600 78.560 ;
        RECT 344.720 76.360 347.695 77.160 ;
        RECT 0.000 75.840 347.695 76.360 ;
        RECT 0.000 74.440 345.600 75.840 ;
        RECT 0.000 73.120 347.695 74.440 ;
        RECT 0.000 71.720 345.600 73.120 ;
        RECT 0.000 70.400 347.695 71.720 ;
        RECT 0.000 69.000 345.600 70.400 ;
        RECT 0.000 67.680 347.695 69.000 ;
        RECT 0.000 67.160 345.600 67.680 ;
        RECT 0.000 64.600 4.880 67.160 ;
        RECT 344.720 66.280 345.600 67.160 ;
        RECT 344.720 64.600 347.695 66.280 ;
        RECT 0.000 28.920 347.695 64.600 ;
        RECT 0.000 26.360 4.880 28.920 ;
        RECT 344.720 26.360 347.695 28.920 ;
        RECT 0.000 17.160 347.695 26.360 ;
        RECT 0.000 14.600 4.880 17.160 ;
        RECT 344.720 14.600 347.695 17.160 ;
        RECT 0.000 9.015 347.695 14.600 ;
      LAYER met4 ;
        RECT 286.415 9.015 293.570 229.665 ;
        RECT 297.470 9.015 308.570 229.665 ;
        RECT 312.470 9.015 323.570 229.665 ;
        RECT 327.470 9.015 337.345 229.665 ;
  END
END sram_wrapper_m
END LIBRARY

